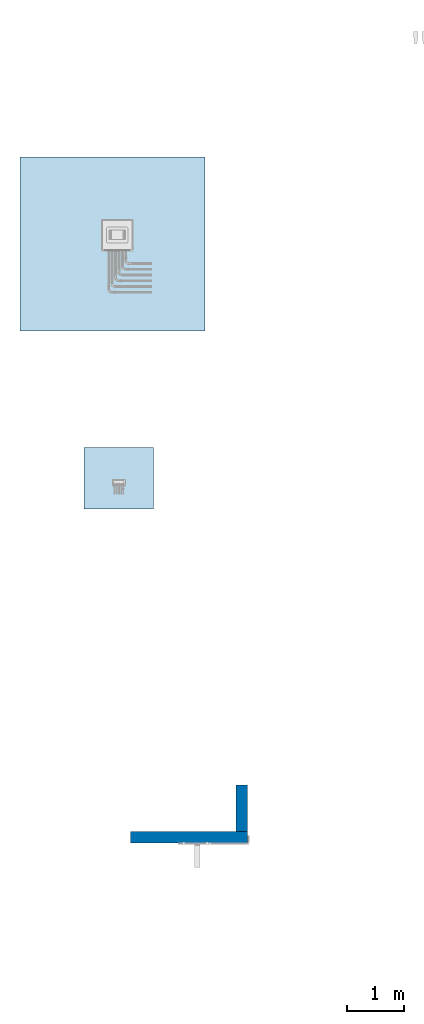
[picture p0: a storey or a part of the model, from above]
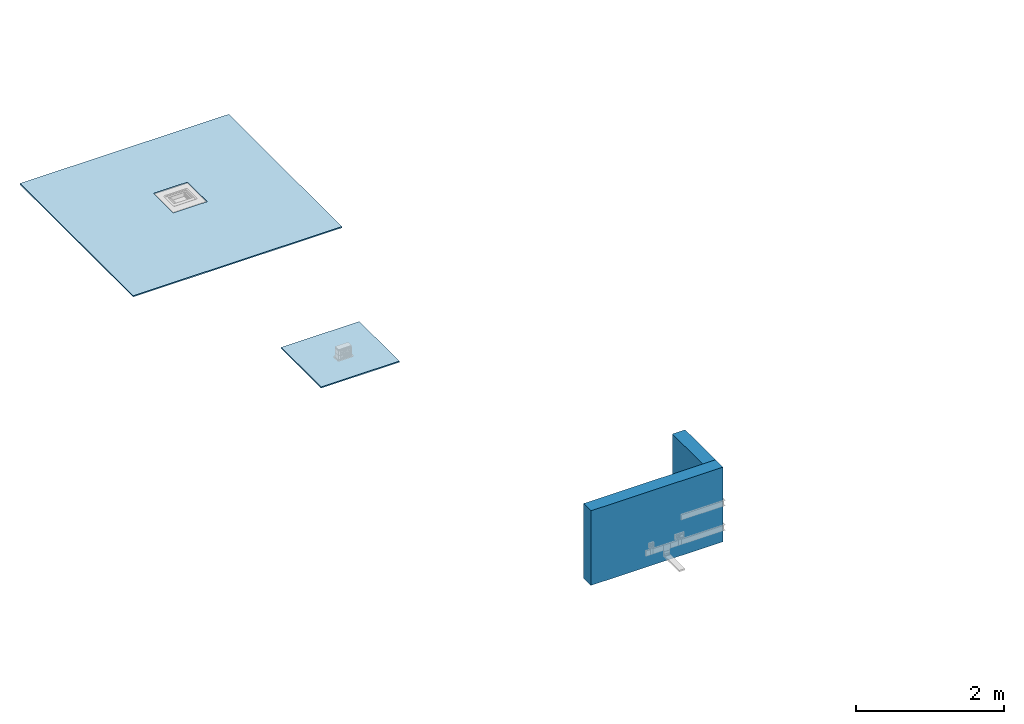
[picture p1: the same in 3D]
Properties of the parts of a building model (IFC2X3)

# File
Description: ViewDefinition [CoordinationView_V2.0]
File name: Номер проекта
Time: 2022-09-15T01:59:56
Written by: The EXPRESS Data Manager Version 5.02.0100.07 : 28 Aug 2013
Made in: 20190225_1515(x64) - Exporter 19.2.10.7 - Альтернативный интерфейс 19.2.10.7
Comment: STEP Physical File produced by: The EXPRESS Data Manager Version 5.02.0100.07 : 28 Aug 2013 * Module: EDMstepFileFactory/EDMstandAlone * Creation date: Thu Sep 15 01:59:56 2022 * Host: Dell * Database: C:\Users\6EDA~1\AppData\Local\Temp\{AB1AB2F8-63A1-4C3A-9AD4-2CAB5618389C}\ifc * Database version: 5507 * Database creation date: Thu Sep 15 01:59:36 2022 * Schema: IFC2X3 * Model: DataRepository.ifc * Model creation date: Thu Sep 15 01:59:37 2022 * Header model: DataRepository.ifc_HeaderModel * Header model creation date: Thu Sep 15 01:59:37 2022 * EDMuser: sdai-user * EDMgroup: sdai-group * License ID and type: 5605 : Permanent license. Expiry date: * EDMstepFileFactory options: 020000

# IfcProject, Номер проекта
LongName: Наименование проекта; Phase: П

# IfcSite, Default
RefLatitude: 55, 44, 57, 789001; RefLongitude: 37, 38, 4, 304809; RefElevation: 0 mm

# IfcBuilding, Наименование здания
LongName: Наименование здания
Pset_BuildingCommon - NumberOfStoreys: 1

# IfcBuildingStorey, Этаж 01
In: Наименование здания
LongName: Этаж 01; Elevation: 0 mm

# IfcBuildingElementProxy: 1 модуль 2 (12)
In: Этаж 01
Pset_BuildingElementProxyCommon - Reference: 1 модуль 2
Name (Суппорт для монтажа ЭУИ серии Viva на DIN-рейку или монтажную плату1:1 модуль 2:...)
554109
554209
554277
554279
554308
554310
554340
554343
554345
554347
554349
554351

# IfcBuildingElementProxy: 2 модуля (2)
In: Этаж 01
Pset_BuildingElementProxyCommon - Reference: 2 модуля
Name
КНС_КаркасДляМонтажаВСтену_ILF_DKC:2 модуля:348239
Переключатели:2 модуля:533907

# IfcBuildingElementProxy: 2 модуля (3)
In: Этаж 01
Type - Material: DKC_Пластик_Белый
Pset_BuildingElementProxyCommon - Reference: 2 модуля
Name
КНС_РамкаУниверсальная_ILF_DKC:2 модуля:505555
КНС_Рамка-суппортAvantiДляЭлектроустановочныхИзделий_ILF_DKC:2 модуля:506528
КНС_КаркасыВСбореСРамкамиViva_ILF_DKC:2 модуля:507383

# IfcBuildingElementProxy: 2 модуля (3)
In: Этаж 01
Type - Material: DKC_Пластик_Серо-черный
Pset_BuildingElementProxyCommon - Reference: 2 модуля
Name
КНС_КаркасДляМонтажаВСистемыОрганизацииРабочихМест_ILF_DKC:2 модуля:347308
КНС_РамкаУниверсальная_ILF_DKC:2 модуля:584864
КНС_Рамка-суппортAvantiДляЭлектроустановочныхИзделий_ILF_DKC:2 модуля:585915

# IfcBuildingElementProxy: 2 модуля (2)
In: Этаж 01
Type - Material: DKC_Пластик_СерыйМеталлик
Pset_BuildingElementProxyCommon - Reference: 2 модуля
Name
КНС_РамкаУниверсальная_ILF_DKC:2 модуля:584843
КНС_Рамка-суппортAvantiДляЭлектроустановочныхИзделий_ILF_DKC:2 модуля:585902

# IfcBuildingElementProxy: 4 модуля (3)
In: Этаж 01
Type - Material: DKC_Пластик_Белый
Pset_BuildingElementProxyCommon - Reference: 4 модуля
Name
КНС_КаркасыВСбореСРамкамиViva_ILF_DKC:4 модуля:561801
КНС_РамкаУниверсальная_ILF_DKC:4 модуля:584867
КНС_Рамка-суппортAvantiДляЭлектроустановочныхИзделий_ILF_DKC:4 модуля:585918

# IfcBuildingElementProxy: 4 модуля (2)
In: Этаж 01
Type - Material: DKC_Пластик_Серо-черный
Pset_BuildingElementProxyCommon - Reference: 4 модуля
Name
КНС_РамкаУниверсальная_ILF_DKC:4 модуля:584873
КНС_Рамка-суппортAvantiДляЭлектроустановочныхИзделий_ILF_DKC:4 модуля:585924

# IfcBuildingElementProxy: 4 модуля (2)
In: Этаж 01
Type - Material: DKC_Пластик_СерыйМеталлик
Pset_BuildingElementProxyCommon - Reference: 4 модуля
Name
КНС_РамкаУниверсальная_ILF_DKC:4 модуля:584870
КНС_Рамка-суппортAvantiДляЭлектроустановочныхИзделий_ILF_DKC:4 модуля:585921

# IfcBuildingElementProxy: 45x45 (5)
In: Этаж 01
Type - Material: DKC_Пластик_Белый
Pset_BuildingElementProxyCommon - Reference: 45x45
Name
КНС_КаркасНа2МодуляДляМонтажаЭлектроустановочныхИзделий_ILF_DKC:45x45:551542
КНС_КаркасНа2МодуляДляМонтажаЭлектроустановочныхИзделий_ILF_DKC:45x45:551564
КНС_КаркасНа2МодуляДляМонтажаЭлектроустановочныхИзделий_ILF_DKC:45x45:554192
КНС_КоробкаМонтажнаяПод2модуляЭлектроустановочныхИзделий_ILF_DKC:45x45:569657
КНС_КаркасНа2МодуляДляМонтажаЭлектроустановочныхИзделий_ILF_DKC:45x45:593066

# IfcBuildingElementProxy: 6 модулей (2)
In: Этаж 01
Type - Material: DKC_Пластик_Белый
Pset_BuildingElementProxyCommon - Reference: 6 модулей
Name
КНС_РамкаУниверсальная_ILF_DKC:6 модулей:584876
КНС_Рамка-суппортAvantiДляЭлектроустановочныхИзделий_ILF_DKC:6 модулей:585927

# IfcBuildingElementProxy: 6 модулей (2)
In: Этаж 01
Type - Material: DKC_Пластик_Серо-черный
Pset_BuildingElementProxyCommon - Reference: 6 модулей
Name
КНС_РамкаУниверсальная_ILF_DKC:6 модулей:584882
КНС_Рамка-суппортAvantiДляЭлектроустановочныхИзделий_ILF_DKC:6 модулей:585933

# IfcBuildingElementProxy: 6 модулей (2)
In: Этаж 01
Type - Material: DKC_Пластик_СерыйМеталлик
Pset_BuildingElementProxyCommon - Reference: 6 модулей
Name
КНС_РамкаУниверсальная_ILF_DKC:6 модулей:584879
КНС_Рамка-суппортAvantiДляЭлектроустановочныхИзделий_ILF_DKC:6 модулей:585930

# IfcBuildingElementProxy: Brava (2)
In: Этаж 01
Type - Material: DKC_Пластик_Белый
Pset_BuildingElementProxyCommon - Reference: Brava
Name
КНС_КоробкаМонтажнаяПод2модуляЭлектроустановочныхИзделий_ILF_DKC:Brava:569663
КНС_КаркасНа2МодуляДляМонтажаЭлектроустановочныхИзделий_ILF_DKC:Brava:638191

# IfcBuildingElementProxy: Brava, КНС_КаркасНа2МодуляДляМонтажаЭлектроустановочныхИзделий_ILF_DKC:Brava:638193
In: Этаж 01
Type - Material: DKC_Пластик_Серо-черный
Pset_BuildingElementProxyCommon - Reference: Brava

# IfcBuildingElementProxy: Viva (2)
In: Этаж 01
Type - Material: DKC_Пластик_Белый
Pset_BuildingElementProxyCommon - Reference: Viva
Name
КНС_КаркасНа2МодуляДляМонтажаЭлектроустановочныхИзделий_ILF_DKC:Viva:493560
КНС_КоробкаМонтажнаяПод2модуляЭлектроустановочныхИзделий_ILF_DKC:Viva:502932

# IfcBuildingElementProxy: Viva (4)
In: Этаж 01
Type - Material: DKC_Пластик_Серо-черный
Pset_BuildingElementProxyCommon - Reference: Viva
Name (КНС_КаркасНа2МодуляДляМонтажаЭлектроустановочныхИзделий_ILF_DKC:Viva:...)
554337
554338
554341
593060

# IfcBuildingElementProxy: Viva, КНС_КаркасНа2МодуляДляМонтажаЭлектроустановочныхИзделий_ILF_DKC:Viva:593057
In: Этаж 01
Type - Material: DKC_Пластик_СерыйМеталлик
Pset_BuildingElementProxyCommon - Reference: Viva

# IfcBuildingElementProxy: Белая (9)
In: Этаж 01
Type - Material: DKC_Пластик_Белый
Pset_BuildingElementProxyCommon - Reference: Белая
Name
КНС_КоробкаМонтажнаяПод4МодуляЭлектроустановочныхИзделийPDD-N120_ILF_DKC:Белая:351623
КНС_КоробкаВСбореССиловойРозеткой_ILF_DKC:Белая:499560
КНС_КоробкаМонтажнаяПод2МодуляЭлектроустановочныхИзделийPDD-N60_ILF_DKC:Белая:502112
КНС_КоробкаМонтажнаяПод2МодуляЭлектроустановочныхИзделийPDD-N60_ILF_DKC:Белая:528202
КНС_КоробкаМонтажнаяПод4МодуляЭлектроустановочныхИзделийPDD-N120_ILF_DKC:Белая:531152
КНС_КоробкаВСбореСВыключателями_ILF_DKC:Белая:564655
КНС_КоробкаВСбореСВыключателями_ILF_DKC:Белая:564673
КНС_КоробкаВСбореСРозеткойRJ-45_ILF_DKC:Белая:566232
КНС_КоробкаВСбореСРозеткойRJ-45_ILF_DKC:Белая:566250

# IfcBuildingElementProxy: Белый (4)
In: Этаж 01
Pset_BuildingElementProxyCommon - Reference: Белый
Name
Силовые электрические розетки, штекерные, с заземлением и со шторками:Белый:530337
Силовые электрические розетки, штекерные, с заземлением и со шторками:Белый:531153
Электрические розетки, штекерные, с заземлением и со шторками, моноблок:Белый:536445
Электрические розетки, штекерные, с заземлением и со шторками, моноблок:Белый:538489

# IfcBuildingElementProxy: Белый (4)
In: Этаж 01
Type - Material: DKC_Пластик_Белый
Pset_BuildingElementProxyCommon - Reference: Белый
Name
КНС_КоробкаРаспределительнаяSDMNДляМини-каналов_ILF_DKC:Белый:503754
КНС_Каркас6МодулейДляМонтажаЭУИСерииViva_ILF_DKC:Белый:536426
КНС_Каркас6МодулейДляМонтажаЭУИСерииViva_ILF_DKC:Белый:538488
КНС_Каркас6МодулейДляМонтажаЭУИСерииViva_ILF_DKC:Белый:589587

# IfcBuildingElementProxy: Вертикальное расширение напольной башенки BUS, Вертикальное расширение напольной башенки BUS:Вертикальное расширение напольной башенки BUS:582681
In: Этаж 01
Type - Material: DKC_Пластик_Белый
Pset_BuildingElementProxyCommon - Reference: Вертикальное расширение напольной башенки BUS

# IfcBuildingElementProxy: Вертикальное расширение напольной башенки BUS (6)
In: Этаж 01
Type - Material: DKC_Пластик_Серо-черный
Pset_BuildingElementProxyCommon - Reference: Вертикальное расширение напольной башенки BUS
Name (Вертикальное расширение напольной башенки BUS:Вертикальное расширение напольной башенки BUS:...)
539299
582692
582693
650173
650179
650180

# IfcBuildingElementProxy: Вертикальное расширение напольной башенки BUS (3)
In: Этаж 01
Type - Material: DKC_Пластик_СерыйМеталлик
Pset_BuildingElementProxyCommon - Reference: Вертикальное расширение напольной башенки BUS
Name (Вертикальное расширение напольной башенки BUS:Вертикальное расширение напольной башенки BUS:...)
650177
650184
650185

# IfcBuildingElementProxy: Категория 5e (12)
In: Этаж 01
Pset_BuildingElementProxyCommon - Reference: Категория 5e
Name (Компьютерные розетки:Категория 5e:...)
551574
554208
554276
554278
554307
554309
554339
554342
554344
554346
554348
554350

# IfcBuildingElementProxy: Комплект пластины для ввода труб в металлическую опалубку (2)
In: Этаж 01
Pset_BuildingElementProxyCommon - Reference: Комплект пластины для ввода труб в металлическую опалубку
Name (Комплект пластины для ввода труб в металлическую опалубку:Комплект пластины для ввода труб в металлическую опалубку:...)
522286
536397

# IfcBuildingElementProxy: Коричневая (6)
In: Этаж 01
Type - Material: DKC_Пластик_Коричневый
Pset_BuildingElementProxyCommon - Reference: Коричневая
Name
КНС_КоробкаВСбореСВыключателями_ILF_DKC:Коричневая:497200
КНС_КоробкаВСбореСРозеткойRJ-45_ILF_DKC:Коричневая:498693
КНС_КоробкаВСбореСВыключателями_ILF_DKC:Коричневая:564663
КНС_КоробкаВСбореСРозеткойRJ-45_ILF_DKC:Коричневая:566247
КНС_КоробкаВСбореССиловойРозеткой_ILF_DKC:Коричневая:567165
КНС_КоробкаМонтажнаяПод2МодуляЭлектроустановочныхИзделийPDD-N60_ILF_DKC:Коричневая:593980

# IfcBuildingElementProxy: Коричневый, КНС_КоробкаРаспределительнаяSDMNДляМини-каналов_ILF_DKC:Коричневый:570533
In: Этаж 01
Type - Material: DKC_Пластик_Коричневый
Pset_BuildingElementProxyCommon - Reference: Коричневый

# IfcBuildingElementProxy: Коробка для настенного монтажа, IP55_ILF_DKC, КНС_КоробкаДляНастенногоМонтажаIP55_ILF_DKC:Коробка для настенного монтажа, IP55_ILF_DKC:354126
In: Этаж 01
Type - Material: DKC_Стекло, DKC_Пластик_Белый
Pset_BuildingElementProxyCommon - Reference: Коробка для настенного монтажа, IP55_ILF_DKC

# IfcBuildingElementProxy: Коробка распределительная настенная Brava_ILF_DKC, КНС_КоробкаРаспределительнаяНастеннаяBrava_ILF_DKC:Коробка распределительная настенная Brava_ILF_DKC:354965
In: Этаж 01
Type - Material: DKC_Пластик_Белый
Pset_BuildingElementProxyCommon - Reference: Коробка распределительная настенная Brava_ILF_DKC

# IfcBuildingElementProxy: Крышка опалубки для установки лючка In-liner Front 12 модулей (2)
In: Этаж 01
Pset_BuildingElementProxyCommon - Reference: Крышка опалубки для установки лючка In-liner Front 12 модулей
Name (Крышка опалубки для установки лючка In-liner Front 12 модулей:Крышка опалубки для установки лючка In-liner Front 12 модулей:...)
538689
639312

# IfcBuildingElementProxy: Крышка опалубки сплошная металлическая, Крышка опалубки сплошная металлическая:Крышка опалубки сплошная металлическая:645387
In: Этаж 01
Pset_BuildingElementProxyCommon - Reference: Крышка опалубки сплошная металлическая

# IfcBuildingElementProxy: Лого, Лого:Лого:474578
In: Этаж 01
Type - Material: DKC_КрасныйЛого
Pset_BuildingElementProxyCommon - Reference: Лого

# IfcBuildingElementProxy: Лючок (2)
In: Этаж 01
Pset_BuildingElementProxyCommon - Reference: Лючок
Name (КНС_ЛючокНапольныйНа12Модулей_ILF_DKC:Лючок:...)
298599
536393

# IfcBuildingElementProxy: Модульная коробка для электроустановочных изделий Brava_ILF_DKC, КНС_МодульнаяКоробкаДляЭлектроустановочныхИзделийBrava_ILF_DKC:Модульная коробка для электроустановочных изделий Brava_ILF_DKC:346504
In: Этаж 01
Pset_BuildingElementProxyCommon - Reference: Модульная коробка для электроустановочных изделий Brava_ILF_DKC

# IfcBuildingElementProxy: Напольная двухсторонняя башенка BUS_ILF_DKC (2)
In: Этаж 01
Type - Material: DKC_Пластик_Белый
Pset_BuildingElementProxyCommon - Reference: Напольная двухсторонняя башенка BUS_ILF_DKC
Name (КНС_НапольнаяДвухсторонняяБашенкаBUS_ILF_DKC:Напольная двухсторонняя башенка BUS_ILF_DKC:...)
582667
582680

# IfcBuildingElementProxy: Напольная двухсторонняя башенка BUS_ILF_DKC (5)
In: Этаж 01
Type - Material: DKC_Пластик_Серо-черный
Pset_BuildingElementProxyCommon - Reference: Напольная двухсторонняя башенка BUS_ILF_DKC
Name (КНС_НапольнаяДвухсторонняяБашенкаBUS_ILF_DKC:Напольная двухсторонняя башенка BUS_ILF_DKC:...)
316175
539298
582691
650157
650170

# IfcBuildingElementProxy: Напольная двухсторонняя башенка BUS_ILF_DKC (3)
In: Этаж 01
Type - Material: DKC_Пластик_СерыйМеталлик
Pset_BuildingElementProxyCommon - Reference: Напольная двухсторонняя башенка BUS_ILF_DKC
Name (КНС_НапольнаяДвухсторонняяБашенкаBUS_ILF_DKC:Напольная двухсторонняя башенка BUS_ILF_DKC:...)
582656
650158
650171

# IfcBuildingElementProxy: Опалубка для лючков металлическая (2)
In: Этаж 01
Pset_BuildingElementProxyCommon - Reference: Опалубка для лючков металлическая
Name (Опалубка для лючков металлическая:Опалубка для лючков металлическая:...)
303958
538438

# IfcBuildingElementProxy: Рамка для монтажа в стены, IP55_ILF_DKC, КНС_РамкаДляМонтажаВСтеныIP55_ILF_DKC:Рамка для монтажа в стены, IP55_ILF_DKC:353287
In: Этаж 01
Type - Material: DKC_Стекло, DKC_Пластик_Белый
Pset_BuildingElementProxyCommon - Reference: Рамка для монтажа в стены, IP55_ILF_DKC

# IfcBuildingElementProxy: Серый, КНС_Каркас6МодулейДляМонтажаЭУИСерииViva_ILF_DKC:Серый:589597
In: Этаж 01
Type - Material: DKC_Пластик_СерыйМеталлик
Pset_BuildingElementProxyCommon - Reference: Серый

# IfcBuildingElementProxy: Суппорт для установки автоматических выключателей в лючок (2)
In: Этаж 01
Pset_BuildingElementProxyCommon - Reference: Суппорт для установки автоматических выключателей в лючок
Name (Суппорт для установки автоматических выключателей в лючок:Суппорт для установки автоматических выключателей в лючок:...)
309185
309186

# IfcBuildingElementProxy: Текст модели:100 мм Arial (112)
In: Этаж 01
Pset_BuildingElementProxyCommon - Reference: 100 мм Arial

# IfcBuildingElementProxy: Текст модели:150 мм Arial (36)
In: Этаж 01
Pset_BuildingElementProxyCommon - Reference: 150 мм Arial

# IfcBuildingElementProxy: Текст модели:300 мм Arial (6)
In: Этаж 01
Pset_BuildingElementProxyCommon - Reference: 300 мм Arial

# IfcBuildingElementProxy: Текст модели:600 мм Arial
In: Этаж 01
Pset_BuildingElementProxyCommon - Reference: 600 мм Arial

# IfcBuildingElementProxy: Черный, КНС_Каркас6МодулейДляМонтажаЭУИСерииViva_ILF_DKC:Черный:492678
In: Этаж 01
Type - Material: DKC_Пластик_Серо-черный
Pset_BuildingElementProxyCommon - Reference: Черный

# IfcDistributionPort (98)
Description: Flow; FlowDirection: SOURCEANDSINK
Name
2 x InPort_530742
OutPort_530996
2 x OutPort_535278
2 x InPort_531154
OutPort_531156
OutPort_531155
InPort_531155
2 x OutPort_535979
InPort_531156
2 x OutPort_534776
InPort_534193
2 x OutPort_535095
2 x InPort_534208
InPort_534776
InPort_535978
InPort_536318
2 x OutPort_536320
InPort_536319
6 x InPort_536393
OutPort_539010
OutPort_539057
OutPort_539133
OutPort_539095
OutPort_538894
OutPort_538848
InPort_538848
OutPort_538956
InPort_538894
2 x OutPort_538913
InPort_538902
InPort_538956
OutPort_538958
InPort_539010
2 x OutPort_539025
InPort_539018
InPort_539057
2 x OutPort_539070
InPort_539065
InPort_539095
2 x OutPort_539108
InPort_539103
InPort_539133
2 x OutPort_539146
InPort_539141
6 x InPort_539298
OutPort_558711
OutPort_558763
OutPort_558897
OutPort_558811
OutPort_558665
OutPort_554395
InPort_554395
2 x OutPort_558607
InPort_558596
InPort_558654
2 x OutPort_558667
InPort_558665
InPort_558702
2 x OutPort_558713
InPort_558711
InPort_558750
2 x OutPort_558765
InPort_558763
InPort_558802
2 x OutPort_558813
InPort_558811
InPort_558886
2 x OutPort_558899
InPort_558897

# IfcFlowFitting: 50х20, 50/2х20, КНС_АдаптерДляВводаКоробовВКоробкиBrava_ILF_DKC:50х20, 50/2х20:491871
In: Этаж 01
Pset_DistributionFlowElementCommon - Reference: 50х20, 50/2х20

# IfcFlowFitting: 70х22, КНС_АдаптерДляВводаКоробовВКоробкиBrava_ILF_DKC:70х22:587617
In: Этаж 01
Pset_DistributionFlowElementCommon - Reference: 70х22

# IfcFlowFitting: 90х25, КНС_АдаптерДляВводаКоробовВКоробкиBrava_ILF_DKC:90х25:587626
In: Этаж 01
Pset_DistributionFlowElementCommon - Reference: 90х25

# IfcFlowFitting: Адаптер, КНС_АдаптерДляВводаКороба70×22ВКоробки_ILF_DKC:Адаптер:408350
In: Этаж 01
Type - Material: DKC_Пластик_Белый
Pset_DistributionFlowElementCommon - Reference: Адаптер

# IfcFlowFitting: Белый (25)
In: Этаж 01
Type - Material: DKC_Пластик_Белый
Pset_DistributionFlowElementCommon - Reference: Белый
Name
КНС_УголВнутренний_ILF_DKC:Белый:396199
КНС_УголВнешний_ILF_DKC:Белый:396216
КНС_НакладкаНаСтыкПрофилейКоробов_ILF_DKC:Белый:396311
КНС_Тройник_ILF_DKC:Белый:464844
КНС_Тройник_ILF_DKC:Белый:534776
КНС_УголВнутренний_ILF_DKC:Белый:535095
КНС_УголВнешний_ILF_DKC:Белый:535979
КНС_УголВнешний_ILF_DKC:Белый:536320
КНС_ВводВСтену_ILF_DKC:Белый:588637
КНС_ВводВСтену_ILF_DKC:Белый:588661
КНС_НакладкаНаСтыкПрофилейКоробов_ILF_DKC:Белый:655147
КНС_НакладкаНаСтыкПрофилейКоробов_ILF_DKC:Белый:655157
КНС_УголВнутренний_ILF_DKC:Белый:660912
КНС_УголВнутренний_ILF_DKC:Белый:660920
КНС_УголВнутренний_ILF_DKC:Белый:660928
КНС_УголВнутренний_ILF_DKC:Белый:660936
КНС_УголВнешний_ILF_DKC:Белый:663013
КНС_УголВнешний_ILF_DKC:Белый:663021
КНС_УголВнешний_ILF_DKC:Белый:663029
КНС_УголВнешний_ILF_DKC:Белый:663037
КНС_Тройник_ILF_DKC:Белый:690574
КНС_Тройник_ILF_DKC:Белый:690582
КНС_Тройник_ILF_DKC:Белый:690590
КНС_Тройник_ILF_DKC:Белый:690598
КНС_ВводВСтену_ILF_DKC:Белый:700174

# IfcFlowFitting: Заглушка (6)
In: Этаж 01
Type - Material: DKC_Пластик
Pset_DistributionFlowElementCommon - Reference: Заглушка
Name (КНС_ЗаглушкаТорцевая_ILF_DKC:Заглушка:...)
677611
685926
685934
685942
685950
685991

# IfcFlowFitting: Металл (12)
In: Этаж 01
Pset_DistributionFlowElementCommon - Reference: Металл
Name (ADSK_Поворот:Металл:...)
538913
538956
539025
539070
539108
539146
558607
558667
558713
558765
558813
558899

# IfcFlowFitting: Накладка на стык фронтальных крышек коробов (6)
In: Этаж 01
Pset_DistributionFlowElementCommon - Reference: Накладка на стык фронтальных крышек коробов
Name (КНС_НакладкаНаСтыкФронтальныхКрышекКоробов_ILF_DKC:Накладка на стык фронтальных крышек коробов:...)
396330
651129
651144
651149
651154
652265

# IfcFlowFitting: Отвод узкий к коробкам (3)
In: Этаж 01
Type - Material: DKC_Пластик_Белый
Pset_DistributionFlowElementCommon - Reference: Отвод узкий к коробкам
Name (КНС_ОтводОтКоробовПлинтусногоТипаККоробкам_ILF_DKC:Отвод узкий к коробкам:...)
504654
530742
531154

# IfcFlowFitting: Отвод широкий к коробкам, КНС_ОтводОтКоробовПлинтусногоТипаККоробкам_ILF_DKC:Отвод широкий к коробкам:597482
In: Этаж 01
Type - Material: DKC_Пластик_Белый
Pset_DistributionFlowElementCommon - Reference: Отвод широкий к коробкам

# IfcFlowFitting: Переходник_ILF_DKC (3)
In: Этаж 01
Pset_DistributionFlowElementCommon - Reference: Переходник_ILF_DKC
Name (КНС_Переходник_ILF_DKC:Переходник_ILF_DKC:...)
402958
693635
693643

# IfcFlowFitting: Серебристый металлик (3)
In: Этаж 01
Type - Material: DKC_Пластик_СерыйМеталлик
Pset_DistributionFlowElementCommon - Reference: Серебристый металлик
Name (КНС_НакладкаНаСтыкПрофилейКоробов_ILF_DKC:Серебристый металлик:...)
655116
655148
655158

# IfcFlowFitting: Угол плоский белый (5)
In: Этаж 01
Type - Material: DKC_Пластик_Белый
Pset_DistributionFlowElementCommon - Reference: Угол плоский белый
Name (КНС_УголПлоский_ILF_DKC:Угол плоский белый:...)
396179
657086
657108
657112
657116

# IfcFlowFitting: Угол плоский черный, КНС_УголПлоский_ILF_DKC:Угол плоский черный:657113
In: Этаж 01
Type - Material: DKC_Пластик_Серо-черный
Pset_DistributionFlowElementCommon - Reference: Угол плоский черный

# IfcFlowFitting: Черный (5)
In: Этаж 01
Type - Material: DKC_Пластик_Серо-черный
Pset_DistributionFlowElementCommon - Reference: Черный
Name
КНС_ВводВСтену_ILF_DKC:Черный:588671
КНС_НакладкаНаСтыкПрофилейКоробов_ILF_DKC:Черный:655149
КНС_УголВнутренний_ILF_DKC:Черный:660968
КНС_УголВнешний_ILF_DKC:Черный:663071
КНС_Тройник_ILF_DKC:Черный:689560

# IfcFlowSegment: Кабельный лоток с соединительными деталями:Кабельный короб плинтусного типа с крышкой (2)
In: Этаж 01
Type - PredefinedType: CABLETRAYSEGMENT
Pset_ManufacturerTypeInformation - Manufacturer: DKC
Pset_DistributionFlowElementCommon - Reference: Кабельный короб плинтусного типа с крышкой
Name (Кабельный лоток с соединительными деталями:Кабельный короб плинтусного типа с крышкой:...)
390669
703041

# IfcFlowSegment: Кабельный лоток с соединительными деталями:Кабельный короб с боковой и фронтальной крышками (10)
In: Этаж 01
Type - PredefinedType: CABLETRAYSEGMENT
Pset_ManufacturerTypeInformation - Manufacturer: DKC
Pset_DistributionFlowElementCommon - Reference: Кабельный короб с боковой и фронтальной крышками
Name (Кабельный лоток с соединительными деталями:Кабельный короб с боковой и фронтальной крышками:...)
464811
530996
531155
531156
534193
534208
535278
535978
536318
536319

# IfcFlowSegment: Кабельный лоток с соединительными деталями:Кабельный короб с фронтальной крышкой Белый (3)
In: Этаж 01
Type - PredefinedType: CABLETRAYSEGMENT
Pset_ManufacturerTypeInformation - Manufacturer: DKC
Pset_DistributionFlowElementCommon - Reference: Кабельный короб с фронтальной крышкой Белый
Name (Кабельный лоток с соединительными деталями:Кабельный короб с фронтальной крышкой Белый:...)
383413
703160
703194

# IfcFlowSegment: Кабельный лоток с соединительными деталями:Кабельный короб с фронтальной крышкой Черный, Кабельный лоток с соединительными деталями:Кабельный короб с фронтальной крышкой Черный:289707
In: Этаж 01
Type - PredefinedType: CABLETRAYSEGMENT
Pset_ManufacturerTypeInformation - Manufacturer: DKC
Pset_DistributionFlowElementCommon - Reference: Кабельный короб с фронтальной крышкой Черный

# IfcFlowSegment: Короб с соединительными деталями:ADSK_Труба водогазопроводная_Стальная (24)
In: Этаж 01
Type - PredefinedType: CONDUITSEGMENT
Pset_DistributionFlowElementCommon - Reference: ADSK_Труба водогазопроводная_Стальная
Name (Короб с соединительными деталями:ADSK_Труба водогазопроводная_Стальная:...)
538848
538894
538902
538958
539010
539018
539057
539065
539095
539103
539133
539141
554395
558596
558654
558665
558702
558711
558750
558763
558802
558811
558886
558897

# IfcSlab: Перекрытие:ADSK_Пол_Условный_20 (2)
In: Этаж 01
PredefinedType: FLOOR; Material: <Unnamed> 20 mm
Pset_SlabCommon - LoadBearing: no; Reference: ADSK_Пол_Условный_20; IsExternal: no
Name (Перекрытие:ADSK_Пол_Условный_20:...)
538550
539465 | Pset_SlabCommon - PitchAngle: 0 deg

# IfcWallStandardCase: Базовая стена:Типовой - 200мм (2)
In: Этаж 01
Type - PredefinedType: STANDARD; Material: <Unnamed> 200 mm
Pset_WallCommon - Reference: Типовой - 200мм; LoadBearing: no; ExtendToStructure: no; IsExternal: yes
Name (Базовая стена:Типовой - 200мм:...)
527918
535839
